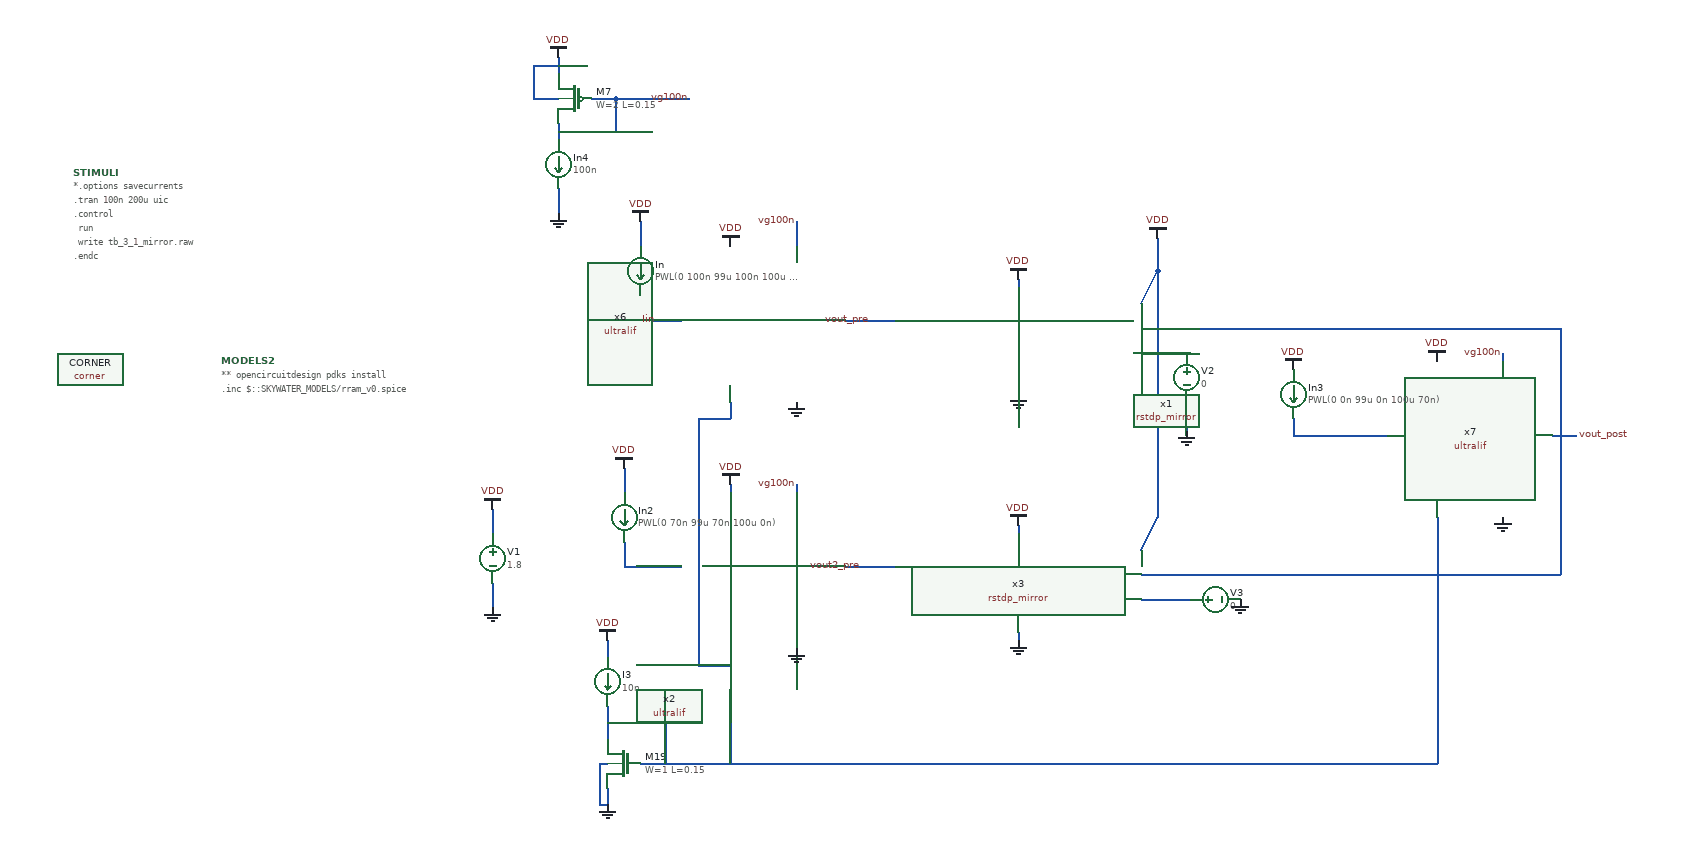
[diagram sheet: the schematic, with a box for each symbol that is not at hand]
v {xschem version=3.4.5 file_version=1.2
}
G {}
K {}
V {}
S {}
E {}
B 2 1390 -105 2190 295 {flags=graph
y1=3.9575762
y2=5.2375762
ypos1=0
ypos2=2
divy=5
subdivy=1
unity=1
x1=1.5625e-11
x2=0.0002
divx=5
subdivx=1
xlabmag=1.0
ylabmag=1.0
node="\\"Fil1; 5 n.x1.x1.xr2.n1#ngap -\\"
\\"Fil2; 5 n.x3.x1.xr2.n1#ngap - \\""
color="4 7"
dataset=-1
unitx=1
logx=0
logy=0
}
B 2 1355 535 2155 935 {flags=graph
y1=-1.1
y2=1.1
ypos1=0
ypos2=2
divy=5
subdivy=1
unity=1
x1=1.5625e-11
x2=0.0002
divx=5
subdivx=1
xlabmag=1.0
ylabmag=1.0


dataset=-1
unitx=1
logx=0
logy=0
color=4
node="\\"Vmem1; x1.x1.BE x1.x1.TE - \\""}
B 2 1300 -750 2100 -350 {flags=graph
y1=0.62
y2=1.6
ypos1=0
ypos2=2
divy=5
subdivy=1
unity=1
x1=1.5625e-11
x2=0.0002
divx=5
subdivx=1
xlabmag=1.0
ylabmag=1.0


dataset=-1
unitx=1
logx=0
logy=0
color=8
node=x7.vm}
B 2 -595 -770 205 -370 {flags=graph
y1=-0.0021
y2=1.9
ypos1=0
ypos2=2
divy=5
subdivy=1
unity=1
x1=1.5625e-11
x2=0.0002
divx=5
subdivx=1
xlabmag=1.0
ylabmag=1.0


dataset=-1
unitx=1
logx=0
logy=0
color="4 6"
node="vout_pre
vout2_pre"}
B 2 300 -720 1100 -320 {flags=graph
y1=-2.6e-08
y2=1.3e-07
ypos1=0
ypos2=2
divy=5
subdivy=1
unity=1
x1=1.5625e-11
x2=0.0002
divx=5
subdivx=1
xlabmag=1.0
ylabmag=1.0


dataset=-1
unitx=1
logx=0
logy=0
color=6
node=i(v2)}
B 2 250 590 1050 990 {flags=graph
y1=-5.6e-06
y2=0.0002
ypos1=0
ypos2=2
divy=5
subdivy=1
unity=1
x1=1.5625e-11
x2=0.0002
divx=5
subdivx=1
xlabmag=1.0
ylabmag=1.0


dataset=-1
unitx=1
logx=0
logy=0
color=6
node=i(v3)}
N -90 320 -90 350 {
lab=GND}
N -90 230 -90 260 {
lab=VDD}
N 50 470 50 510 {
lab=#net1}
N 50 390 50 410 {
lab=VDD}
N 50 570 50 590 {
lab=GND}
N 40 540 50 540 {
lab=GND}
N 40 540 40 590 {
lab=GND}
N 40 590 50 590 {
lab=GND}
N 90 540 160 540 {
lab=#net1}
N 50 490 120 490 {
lab=#net1}
N 120 490 120 540 {
lab=#net1}
N 720 -100 720 -60 {
lab=VDD}
N 550 -50 550 -40 {
lab=VDD}
N 340 0 400 0 {
lab=vout_pre}
N 550 80 550 90 {
lab=GND}
N 90 0 140 0 {
lab=Iin}
N 90 -30 90 0 {
lab=Iin}
N 90 -120 90 -90 {
lab=VDD}
N 700 -20 720 -60 {
lab=VDD}
N 280 540 940 540 {
lab=#net1}
N 200 510 200 540 {
lab=#net1}
N 70 270 70 300 {
lab=#net2}
N 70 180 70 210 {
lab=VDD}
N 70 300 140 300 {
lab=#net2}
N 200 400 200 510 {
lab=#net1}
N 160 420 200 420 {
lab=#net1}
N 160 120 160 420 {
lab=#net1}
N 160 120 200 120 {
lab=#net1}
N 200 100 200 120 {
lab=#net1}
N 200 200 200 210 {
lab=VDD}
N 550 250 550 260 {
lab=VDD}
N 550 380 550 390 {
lab=GND}
N 340 300 400 300 {
lab=vout2_pre}
N 1200 140 1230 140 {
lab=vout_post}
N 1060 240 1060 540 {
lab=#net1}
N 940 540 950 540 {
lab=#net1}
N 1210 140 1210 310 {
lab=vout_post}
N 930 10 1210 10 {
lab=vout_post}
N 1210 10 1210 140 {
lab=vout_post}
N 720 200 720 240 {
lab=VDD}
N 700 280 720 240 {
lab=VDD}
N 720 -60 720 200 {
lab=VDD}
N -10 -320 -10 -300 {
lab=VDD}
N -40 -270 -10 -270 {
lab=VDD}
N -40 -310 -40 -270 {
lab=VDD}
N -40 -310 -10 -310 {
lab=VDD}
N 30 -270 60 -270 {
lab=vg100n}
N -10 -240 -10 -220 {
lab=vg100n}
N -10 -160 -10 -130 {
lab=GND}
N -10 -230 60 -230 {
lab=vg100n}
N 60 -270 60 -230 {
lab=vg100n}
N 60 -270 150 -270 {
lab=vg100n}
N 280 -120 280 -90 {
lab=vg100n}
N 280 200 280 210 {
lab=vg100n}
N 1140 40 1140 50 {
lab=vg100n}
N 700 10 820 10 {
lab=vout_post}
N 160 540 280 540 {
lab=#net1}
N 1100 310 1210 310 {
lab=vout_post}
N 950 540 1060 540 {
lab=#net1}
N 820 10 930 10 {
lab=vout_post}
N 700 310 1100 310 {
lab=vout_post}
N 970 140 1000 140 {
lab=#net3}
N 700 40 760 40 {
lab=#net4}
N 700 340 760 340 {
lab=#net5}
N 755 100 755 140 {
lab=#net6}
N 885 120 885 140 {
lab=#net3}
N 885 140 970 140 {
lab=#net3}
C {devices/vsource.sym} -90 290 0 0 {name=V1 value=1.8 savecurrent=false}
C {devices/vdd.sym} -90 230 0 0 {name=l1 lab=VDD}
C {devices/gnd.sym} -90 350 0 0 {name=l2 lab=GND}
C {sky130_fd_pr/corner.sym} -580 60 0 0 {name=CORNER only_toplevel=true corner=tt}
C {devices/code_shown.sym} -600 -180 0 0 {name=STIMULI 
only_toplevel=true
place=end
value="
*.options savecurrents
.tran 100n 200u uic
.control
	run
	write tb_3_1_mirror.raw
.endc
"}
C {devices/code.sym} -420 50 0 0 {name=MODELS2
only_toplevel=true
format="tcleval( @value )"
value="
** opencircuitdesign pdks install
.inc $::SKYWATER_MODELS/rram_v0.spice
"
spice_ignore=false}
C {/home/alex/Desktop/EDA/SNN_IPN/Neuron/ultralif/ultralif.sym} 240 0 0 0 {name=x6}
C {/home/alex/Desktop/EDA/SNN_IPN/Neuron/ultralif/ultralif.sym} 1100 140 0 0 {name=x7}
C {sky130_fd_pr/nfet_01v8.sym} 70 540 0 1 {name=M19
L=0.15
W=1
nf=1 
mult=1
ad="'int((nf+1)/2) * W/nf * 0.29'" 
pd="'2*int((nf+1)/2) * (W/nf + 0.29)'"
as="'int((nf+2)/2) * W/nf * 0.29'" 
ps="'2*int((nf+2)/2) * (W/nf + 0.29)'"
nrd="'0.29 / W'" nrs="'0.29 / W'"
sa=0 sb=0 sd=0
model=nfet_01v8
spiceprefix=X
}
C {devices/isource.sym} 50 440 0 0 {name=I3 value=10n}
C {devices/vdd.sym} 50 390 0 0 {name=l30 lab=VDD}
C {devices/gnd.sym} 50 590 0 0 {name=l31 lab=GND}
C {devices/vdd.sym} 200 -90 0 0 {name=l3 lab=VDD}
C {devices/gnd.sym} 280 100 0 0 {name=l4 lab=GND}
C {devices/gnd.sym} 1140 240 0 0 {name=l5 lab=GND}
C {devices/vdd.sym} 1060 50 0 0 {name=l6 lab=VDD}
C {devices/vdd.sym} 550 -50 0 0 {name=l10 lab=VDD}
C {devices/gnd.sym} 550 90 0 0 {name=l11 lab=GND}
C {devices/lab_pin.sym} 110 0 3 0 {name=p2 sig_type=std_logic lab=Iin}
C {devices/isource.sym} 90 -60 0 1 {name=In value="PWL(0 100n 99u 100n 100u 0n)"}
C {devices/vdd.sym} 90 -120 0 0 {name=l52 lab=VDD}
C {devices/lab_pin.sym} 370 0 1 0 {name=p1 sig_type=std_logic lab=vout_pre}
C {devices/lab_pin.sym} 1230 140 0 1 {name=p3 sig_type=std_logic lab=vout_post}
C {devices/launcher.sym} -400 255 0 0 {name=h5
descr="load waves" 
tclcommand="xschem raw_read $netlist_dir/tb_3_1_mirror.raw tran"
}
C {/home/alex/Desktop/EDA/SNN_IPN/Neuron/ultralif/ultralif.sym} 240 300 0 0 {name=x2}
C {devices/gnd.sym} 280 400 0 0 {name=l7 lab=GND}
C {devices/isource.sym} 70 240 0 1 {name=In2 value="PWL(0 70n 99u 70n 100u 0n)" }
C {devices/vdd.sym} 70 180 0 0 {name=l12 lab=VDD}
C {devices/vdd.sym} 200 200 0 0 {name=l13 lab=VDD}
C {devices/vdd.sym} 550 250 0 0 {name=l14 lab=VDD}
C {devices/gnd.sym} 550 390 0 0 {name=l15 lab=GND}
C {devices/lab_pin.sym} 360 300 1 0 {name=p5 sig_type=std_logic lab=vout2_pre}
C {devices/vdd.sym} 720 -100 0 0 {name=l9 lab=VDD}
C {sky130_fd_pr/pfet_01v8.sym} 10 -270 0 1 {name=M7
L=0.15
W=2
nf=1
mult=1
ad="'int((nf+1)/2) * W/nf * 0.29'" 
pd="'2*int((nf+1)/2) * (W/nf + 0.29)'"
as="'int((nf+2)/2) * W/nf * 0.29'" 
ps="'2*int((nf+2)/2) * (W/nf + 0.29)'"
nrd="'0.29 / W'" nrs="'0.29 / W'"
sa=0 sb=0 sd=0
model=pfet_01v8
spiceprefix=X
}
C {devices/vdd.sym} -10 -320 0 0 {name=l8 lab=VDD}
C {devices/isource.sym} -10 -190 0 1 {name=In4 value=100n }
C {devices/gnd.sym} -10 -130 0 0 {name=l17 lab=GND}
C {devices/lab_pin.sym} 150 -270 3 0 {name=p7 sig_type=std_logic lab=vg100n}
C {devices/lab_pin.sym} 280 -120 1 0 {name=p8 sig_type=std_logic lab=vg100n}
C {devices/lab_pin.sym} 280 200 1 0 {name=p9 sig_type=std_logic lab=vg100n}
C {devices/lab_pin.sym} 1140 40 1 0 {name=p11 sig_type=std_logic lab=vg100n}
C {/home/alex/Desktop/EDA/SNN_IPN/Synapse/rstdp_mirror.sym} 550 0 0 0 {name=x1}
C {/home/alex/Desktop/EDA/SNN_IPN/Synapse/rstdp_mirror.sym} 550 300 0 0 {name=x3}
C {devices/vsource.sym} 755 70 0 0 {name=V2 value=0 }
C {devices/vsource.sym} 790 340 3 0 {name=V3 value=0 }
C {devices/vdd.sym} 885 60 0 0 {name=l16 lab=VDD}
C {devices/isource.sym} 885 90 0 1 {name=In3 value="PWL(0 0n 99u 0n 100u 70n)"}
C {devices/gnd.sym} 820 340 0 0 {name=l18 lab=GND}
C {devices/gnd.sym} 755 135 0 0 {name=l19 lab=GND}
